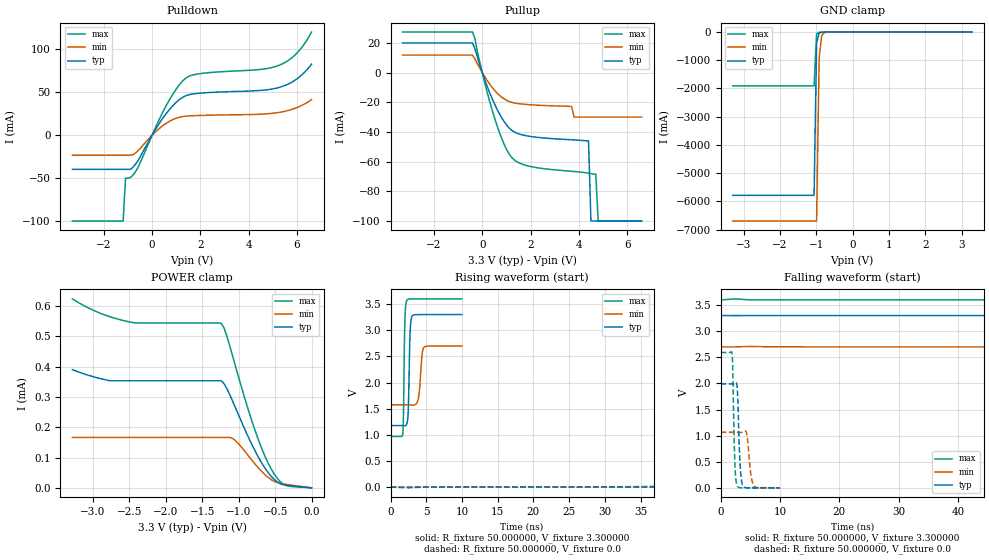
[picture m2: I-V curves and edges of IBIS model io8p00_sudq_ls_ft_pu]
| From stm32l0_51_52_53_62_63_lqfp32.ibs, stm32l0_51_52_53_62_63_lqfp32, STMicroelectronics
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|   Model io8p00_sudq_ls_ft_pu
[Model]  io8p00_sudq_ls_ft_pu
Model_type I/O
Polarity   Non-Inverting
Enable   Active-Low
Vinl =   0.990000V
Vinh =   2.310000V
Vmeas =  1.650000V
Cref =   50.000000pF
Rref =   100.000000M
Vref =   0.0V
C_comp   2.343000pF   2.309800pF   2.393900pF
[Temperature Range]   25.000000   0.125000k   -40.000000
[Pullup Reference]   3.300000V   2.700000V   3.600000V
[Pulldown Reference]   0.0V   0.0V   0.0V
[POWER Clamp Reference]   3.300000V   2.700000V   3.600000V
[GND Clamp Reference]   0.0V   0.0V   0.0V
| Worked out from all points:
|   slope of the pulldown table from 0 to 0.495 V, typ, clamps not added: 22.6 ohm
|   slope of the pullup table from 0 to 0.495 V, typ, clamps not added: 23.9 ohm
|   GND clamp passes 1 mA (typ) near -0.64 V on its own axis
|   rising waveform, R_fixture 50.000000, V_fixture 3.300000: 20-80 % time 207ps typ, 361ps min, 164ps max; typ from 1.18 V to 3.3 V
|   rising waveform, R_fixture 50.000000, V_fixture 0.0: 20-80 % time 205ns typ, 428ns min, 99.8ns max; typ from 0.001 V to 1.99 V
|   falling waveform, R_fixture 50.000000, V_fixture 3.300000: 20-80 % time 193ns typ, 383ns min, 106ns max; typ from 3.3 V to 1.18 V
|   falling waveform, R_fixture 50.000000, V_fixture 0.0: 20-80 % time 384ps typ, 554ps min, 307ps max; typ from 1.99 V to 0.001 V
[Pulldown]
|Voltage   I(typ)   I(min)   I(max)
-3.3V     -39.8mA    -23.38mA   -100mA
-1.2V     -39.8mA    -23.38mA   -100mA
-1.1V     -39.8mA    -23.38mA   -50.11mA
-900mV    -39.8mA    -23.38mA   -49.43mA
-700mV    -34.25mA   -21mA      -43.13mA
600mV     25.84mA    14.18mA    35.34mA
1V        38.32mA    19.82mA    53.81mA
1.4V      46.09mA    22.19mA    66.63mA
2V        49.05mA    23.02mA    71.83mA
5.2V      55.23mA    26.32mA    80.92mA
6V        65.77mA    32.26mA    95.84mA
6.6V      82.81mA    41.44mA    120.2mA
[Pullup]
|Voltage   I(typ)   I(min)   I(max)
-3.3V     19.9mA     11.73mA    27.27mA
-400mV    19.9mA     11.73mA    27.27mA
500mV     -20.88mA   -11.78mA   -30.07mA
1.2V      -38.62mA   -19.99mA   -56.79mA
1.9V      -42.8mA    -21.61mA   -62.92mA
3.7V      -45.29mA   -22.8mA    -66.51mA
3.8V      -45.39mA   -30mA      -66.64mA
4.4V      -46.01mA   -30mA      -67.77mA
4.5V      -100mA     -30mA      -68.06mA
4.7V      -100mA     -30mA      -68.4mA
4.8V      -100mA     -30mA      -100mA
6.6V      -100mA     -30mA      -100mA
[GND_clamp]
|Voltage   I(typ)   I(min)   I(max)
-3.3V     -5.787A    -6.696A    -1.906A
-1.06V    -5.787A    -6.696A    -1.906A
-990mV    -393.4mA   -6.696A    -70.75mA
-920mV    -33.02mA   -919.4mA   -10.9mA
-850mV    -6.829mA   -131.3mA   -6.521mA
-780mV    -3.478mA   -21.06mA   -4.208mA
3.28V     0A         0A         0A
[POWER_clamp]
|Voltage   I(typ)   I(min)   I(max)
-3.28V    390.5uA    166.4uA    624.1uA
-2.76V    353.6uA    166.4uA    564.6uA
-2.44V    353.6uA    166.4uA    545.3uA
-1.24V    353.6uA    166.4uA    543.5uA
-1.2V     344.2uA    166.4uA    528.2uA
-1.16V    327.1uA    166.4uA    499.5uA
-1.04V    262.6uA    155.2uA    398.8uA
-760mV    115.1uA    74.4uA     179.3uA
-560mV    39.86uA    27.94uA    65.07uA
-440mV    15uA       15.53uA    23.15uA
-360mV    8.745uA    12.05uA    9.089uA
0V        0A         0A         0A
[Ramp]
| variable   typ   min   max
dV/dt_r  1.19492/0.20471u   0.61229/0.42891u   1.55547/99.69141n
dV/dt_f  1.27200/0.19325u   0.63468/0.38283u   1.57747/0.10603u
R_load = 50.000000
[Rising Waveform]
R_fixture= 50.000000
V_fixture= 3.300000
V_fixture_min= 2.700000
V_fixture_max= 3.600000
|time   V(typ)   V(min)   V(max)
0s        1.178V     1.575V     970.9mV
1.702ns   1.178V     1.575V     1.018V
2.002ns   1.174V     1.575V     3.173V
2.282ns   1.215V     1.575V     3.571V
2.482ns   1.501V     1.575V     3.593V
2.743ns   2.98V      1.574V     3.598V
3.023ns   3.271V     1.57V      3.599V
3.904ns   3.299V     1.704V     3.599V
4.665ns   3.3V       2.672V     3.6V
9.97ns    3.3V       2.7V       3.6V
[Rising Waveform]
R_fixture= 50.000000
V_fixture= 0.0
V_fixture_min= 0.0
V_fixture_max= 0.0
|time   V(typ)   V(min)   V(max)
0s        1.061mV    1.816mV    656.8uV
50.05ns   4.552mV    4.549mV    91.28mV
100.1ns   80.19mV    4.692mV    919.5mV
165.2ns   461.5mV    7.663mV    1.935V
205.2ns   750.2mV    22.6mV     2.293V
255.3ns   1.09V      59.64mV    2.486V
385.4ns   1.671V     240.3mV    2.58V
505.5ns   1.883V     450.5mV    2.592V
823.3ns   1.986V     877.2mV    2.593V
1.246us   1.993V     1.064V     2.593V
[Falling Waveform]
R_fixture= 50.000000
V_fixture= 3.300000
V_fixture_min= 2.700000
V_fixture_max= 3.600000
|time   V(typ)   V(min)   V(max)
0s        3.3V       2.7V       3.6V
85.09ns   3.3V       2.7V       3.477V
145.1ns   3.215V     2.7V       2.595V
210.2ns   2.869V     2.697V     1.634V
247.7ns   2.614V     2.687V     1.255V
282.8ns   2.365V     2.669V     1.096V
392.9ns   1.648V     2.554V     1V
488ns     1.351V     2.4V       982.1mV
808.3ns   1.2V       1.82V      971.6mV
1.246us   1.178V     1.575V     970.9mV
[Falling Waveform]
R_fixture= 50.000000
V_fixture= 0.0
V_fixture_min= 0.0
V_fixture_max= 0.0
|time   V(typ)   V(min)   V(max)
0s        1.993V     1.064V     2.593V
1.922ns   1.993V     1.064V     2.565V
2.022ns   1.992V     1.064V     2.313V
2.382ns   1.997V     1.064V     499.2mV
2.783ns   1.917V     1.064V     41.24mV
3.243ns   509.5mV    1.064V     2.891mV
3.664ns   60.15mV    1.066V     891.9uV
4.404ns   2.172mV    1.027V     746.8uV
5.546ns   1.117mV    47.38mV    695.1uV
9.97ns    1.061mV    1.816mV    656.8uV
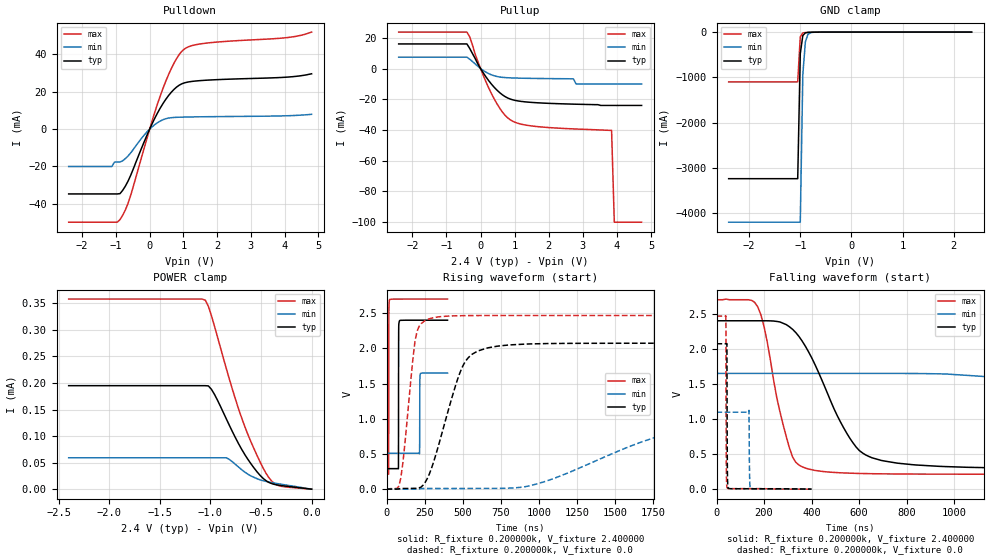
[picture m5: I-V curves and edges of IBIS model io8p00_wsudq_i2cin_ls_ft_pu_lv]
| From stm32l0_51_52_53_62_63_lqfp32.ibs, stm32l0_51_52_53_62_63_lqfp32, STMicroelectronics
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|   Model io8p00_wsudq_i2cin_ls_ft_pu_lv
[Model]  io8p00_wsudq_i2cin_ls_ft_pu_lv
Model_type I/O
Polarity   Non-Inverting
Enable   Active-Low
Vinl =   0.720000V
Vinh =   1.680000V
Vmeas =  1.200000V
Cref =   50.000000pF
Rref =   100.000000M
Vref =   0.0V
C_comp   2.943600pF   2.919700pF   2.965100pF
[Temperature Range]   25.000000   0.105000k   -40.000000
[Pullup Reference]   2.400000V   1.650000V   2.700000V
[Pulldown Reference]   0.0V   0.0V   0.0V
[POWER Clamp Reference]   2.400000V   1.650000V   2.700000V
[GND Clamp Reference]   0.0V   0.0V   0.0V
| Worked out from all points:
|   slope of the pulldown table from 0 to 0.36 V, typ, clamps not added: 28.5 ohm
|   slope of the pullup table from 0 to 0.36 V, typ, clamps not added: 32.2 ohm
|   GND clamp passes 1 mA (typ) near -0.65 V on its own axis
|   rising waveform, R_fixture 0.200000k, V_fixture 2.400000: 20-80 % time 676ps typ, 843ps min, 761ps max; typ from 0.292 V to 2.4 V
|   rising waveform, R_fixture 0.200000k, V_fixture 0.0: 20-80 % time 170ns typ, 820ns min, 66.7ns max; typ from 0.001 V to 2.07 V
|   falling waveform, R_fixture 0.200000k, V_fixture 2.400000: 20-80 % time 180ns typ, 729ns min, 89.6ns max; typ from 2.4 V to 0.292 V
|   falling waveform, R_fixture 0.200000k, V_fixture 0.0: 20-80 % time 1.27ns typ, 1.78ns min, 1.06ns max; typ from 2.07 V to 0.001 V
[Pulldown]
|Voltage   I(typ)   I(min)   I(max)
-2.4V     -34.7mA    -20mA      -49.82mA
-1.12V    -34.7mA    -20mA      -49.82mA
-1.04V    -34.7mA    -17.61mA   -49.82mA
-880mV    -34.55mA   -17.61mA   -48.46mA
-560mV    -24.65mA   -12.68mA   -35.33mA
0V        0A         0A         0A
400mV     13.84mA    5.066mA    22.03mA
720mV     21.25mA    6.254mA    35.26mA
1.04V     24.83mA    6.464mA    43.02mA
1.6V      26.11mA    6.627mA    45.88mA
4V        27.76mA    7.125mA    48.87mA
4.8V      29.63mA    7.94mA     51.96mA
[Pullup]
|Voltage   I(typ)   I(min)   I(max)
-2.4V     16.03mA    7.415mA    23.74mA
-400mV    16.03mA    7.415mA    23.74mA
80mV      -2.838mA   -1.261mA   -4.478mA
320mV     -10.16mA   -4.078mA   -16.34mA
640mV     -17.08mA   -5.718mA   -28.28mA
960mV     -20.45mA   -6.128mA   -34.49mA
1.76V     -22.39mA   -6.47mA    -37.97mA
2.72V     -23.16mA   -6.7mA     -39.27mA
2.8V      -23.2mA    -10mA      -39.35mA
3.84V     -24mA      -10mA      -40.2mA
3.92V     -24mA      -10mA      -100mA
4.72V     -24mA      -10mA      -100mA
[GND_clamp]
|Voltage   I(typ)   I(min)   I(max)
-2.4V     -3.237A    -4.198A    -1.1A
-1.05V    -3.237A    -4.198A    -1.1A
-1V       -475.8mA   -4.198A    -104.2mA
-950mV    -76.24mA   -935.4mA   -18.39mA
-900mV    -16.61mA   -212.9mA   -9.105mA
-850mV    -6.547mA   -50.94mA   -6.589mA
-800mV    -3.998mA   -13.81mA   -4.86mA
-650mV    -1.043mA   -1.182mA   -1.146mA
2.35V     0A         0A         0A
[POWER_clamp]
|Voltage   I(typ)   I(min)   I(max)
-2.4V     195uA      59.14uA    358.2uA
-1.05V    195uA      59.14uA    356uA
-1.02V    194.5uA    59.14uA    344.5uA
-960mV    178.7uA    59.14uA    307.4uA
-840mV    131.4uA    59.14uA    225.5uA
-690mV    74.82uA    36.58uA    133.7uA
-600mV    48.08uA    24.92uA    89.53uA
-510mV    26.23uA    17.69uA    51.64uA
-450mV    15.91uA    14.53uA    29.77uA
-390mV    10.19uA    12.23uA    14.39uA
-330mV    7.608uA    10.24uA    6.963uA
0V        0A         0A         0A
[Ramp]
| variable   typ   min   max
dV/dt_r  0.65095/0.30115u   0.19035/0.81858u   1.03799/0.14356u
dV/dt_f  0.75618/0.32152u   0.19644/0.84673u   1.13779/0.15984u
R_load = 50.000000
[Rising Waveform]
R_fixture= 0.200000k
V_fixture= 2.400000
V_fixture_min= 1.650000
V_fixture_max= 2.700000
|time   V(typ)   V(min)   V(max)
0s        292mV      510.8mV    213.5mV
14.01ns   292mV      510.8mV    220.4mV
15.22ns   292mV      510.8mV    2.419V
19.22ns   292mV      510.8mV    2.687V
77.68ns   290.2mV    510.8mV    2.7V
79.68ns   2.256V     510.8mV    2.7V
84.08ns   2.386V     510.8mV    2.7V
216.2ns   2.4V       506mV      2.7V
221.8ns   2.4V       1.638V     2.7V
400ns     2.4V       1.65V      2.7V
[Rising Waveform]
R_fixture= 0.200000k
V_fixture= 0.0
V_fixture_min= 0.0
V_fixture_max= 0.0
|time   V(typ)   V(min)   V(max)
0s        1.171mV    2.207mV    629.1uV
93.43ns   10.52mV    2.207mV    156.3mV
200.2ns   13.28mV    2.207mV    2.243V
266.9ns   150.1mV    9.996mV    2.408V
347ns     668.1mV    9.997mV    2.449V
533.9ns   1.862V     10.12mV    2.465V
920.9ns   2.062V     40.68mV    2.467V
1.949us   2.073V     854.1mV    2.467V
2.696us   2.073V     1.055V     2.467V
13.33us   2.073V     1.097V     2.467V
[Falling Waveform]
R_fixture= 0.200000k
V_fixture= 2.400000
V_fixture_min= 1.650000
V_fixture_max= 2.700000
|time   V(typ)   V(min)   V(max)
0s        2.4V       1.65V      2.7V
173.5ns   2.4V       1.65V      2.598V
320.3ns   2.277V     1.65V      457.3mV
520.5ns   964.7mV    1.65V      234mV
627.3ns   488.6mV    1.65V      222.7mV
827.5ns   348.5mV    1.649V     215.8mV
1.335us   298.6mV    1.507V     213.6mV
2.202us   292.3mV    723.9mV    213.5mV
2.829us   292mV      567.8mV    213.5mV
13.33us   292mV      510.8mV    213.5mV
[Falling Waveform]
R_fixture= 0.200000k
V_fixture= 0.0
V_fixture_min= 0.0
V_fixture_max= 0.0
|time   V(typ)   V(min)   V(max)
0s        2.073V     1.097V     2.467V
39.24ns   2.073V     1.097V     2.471V
41.24ns   2.073V     1.097V     298.9mV
43.64ns   2.071V     1.097V     33.15mV
44.84ns   728.6mV    1.097V     20.42mV
48.85ns   20.84mV    1.097V     10.89mV
136.5ns   6.533mV    1.123V     8.385mV
139.3ns   6.534mV    162mV      8.381mV
143.3ns   6.534mV    9.087mV    8.377mV
400ns     1.171mV    2.207mV    629.1uV
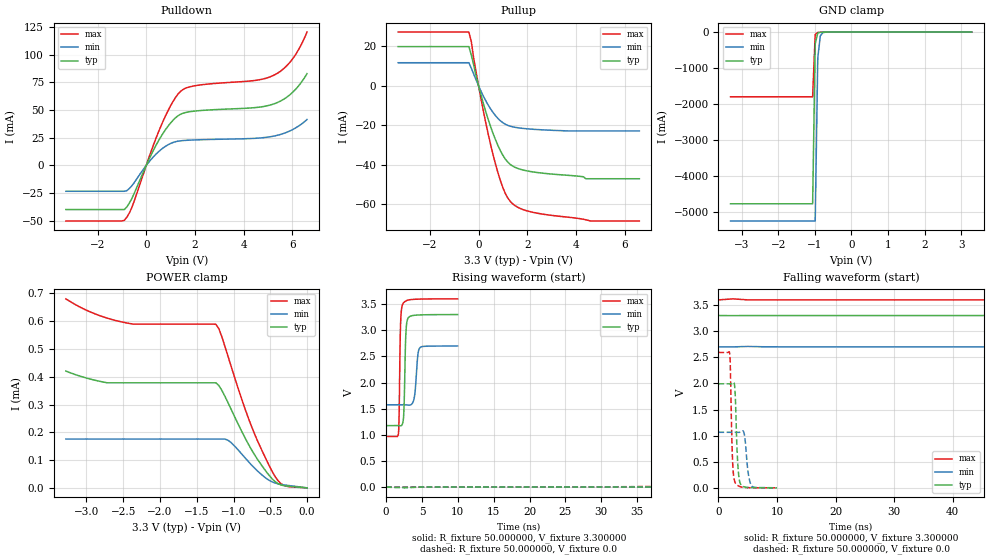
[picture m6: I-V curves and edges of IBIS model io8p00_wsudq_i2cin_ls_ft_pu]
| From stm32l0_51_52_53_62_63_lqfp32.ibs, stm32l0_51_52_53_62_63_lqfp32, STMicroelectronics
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|   Model io8p00_wsudq_i2cin_ls_ft_pu
[Model]  io8p00_wsudq_i2cin_ls_ft_pu
Model_type I/O
Polarity   Non-Inverting
Enable   Active-Low
Vinl =   0.990000V
Vinh =   2.310000V
Vmeas =  1.650000V
Cref =   50.000000pF
Rref =   100.000000M
Vref =   0.0V
C_comp   3.020400pF   2.988200pF   3.054500pF
[Temperature Range]   25.000000   0.125000k   -40.000000
[Pullup Reference]   3.300000V   2.700000V   3.600000V
[Pulldown Reference]   0.0V   0.0V   0.0V
[POWER Clamp Reference]   3.300000V   2.700000V   3.600000V
[GND Clamp Reference]   0.0V   0.0V   0.0V
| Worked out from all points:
|   slope of the pulldown table from 0 to 0.495 V, typ, clamps not added: 22.6 ohm
|   slope of the pullup table from 0 to 0.495 V, typ, clamps not added: 23.9 ohm
|   GND clamp passes 1 mA (typ) near -0.64 V on its own axis
|   rising waveform, R_fixture 50.000000, V_fixture 3.300000: 20-80 % time 222ps typ, 369ps min, 182ps max; typ from 1.18 V to 3.3 V
|   rising waveform, R_fixture 50.000000, V_fixture 0.0: 20-80 % time 204ns typ, 424ns min, 99.2ns max; typ from 0.001 V to 1.99 V
|   falling waveform, R_fixture 50.000000, V_fixture 3.300000: 20-80 % time 192ns typ, 379ns min, 105ns max; typ from 3.3 V to 1.18 V
|   falling waveform, R_fixture 50.000000, V_fixture 0.0: 20-80 % time 410ps typ, 575ps min, 333ps max; typ from 1.99 V to 0.001 V
[Pulldown]
|Voltage   I(typ)   I(min)   I(max)
-3.3V     -39.83mA   -23.36mA   -50.2mA
-900mV    -39.83mA   -23.36mA   -49.52mA
-600mV    -30.28mA   -18.59mA   -38.45mA
100mV     4.867mA    2.821mA    6.48mA
600mV     25.85mA    14.17mA    35.39mA
1V        38.33mA    19.81mA    53.88mA
1.4V      46.1mA     22.18mA    66.72mA
2V        49.07mA    23.02mA    71.93mA
4.4V      52.05mA    24.38mA    76.53mA
5.2V      55.25mA    26.3mA     81.02mA
6V        65.78mA    32.24mA    95.96mA
6.6V      82.83mA    41.41mA    120.4mA
[Pullup]
|Voltage   I(typ)   I(min)   I(max)
-3.3V     19.9mA     11.73mA    27.27mA
-400mV    19.9mA     11.73mA    27.27mA
-300mV    15.74mA    8.978mA    22.52mA
-200mV    10.44mA    5.968mA    13.84mA
200mV     -9.115mA   -5.294mA   -12.98mA
600mV     -24.29mA   -13.56mA   -35.12mA
1V        -35.2mA    -18.69mA   -51.63mA
1.2V      -38.62mA   -19.99mA   -56.79mA
1.4V      -40.6mA    -20.72mA   -59.71mA
2.2V      -43.48mA   -21.92mA   -63.91mA
4.6V      -47mA      -22.8mA    -68.4mA
6.6V      -47mA      -22.8mA    -68.4mA
[GND_clamp]
|Voltage   I(typ)   I(min)   I(max)
-3.3V     -4.766A    -5.244A    -1.797A
-1.06V    -4.766A    -5.244A    -1.797A
-990mV    -326.6mA   -5.244A    -67.9mA
-920mV    -28.92mA   -722.1mA   -10.96mA
-850mV    -6.612mA   -104.2mA   -6.532mA
-780mV    -3.464mA   -17.27mA   -4.209mA
-500mV    -57.88uA   -167.8uA   -34.02uA
3.28V     0A         0A         0A
[POWER_clamp]
|Voltage   I(typ)   I(min)   I(max)
-3.28V    420.5uA    175.8uA    680.6uA
-2.72V    378.4uA    175.8uA    611.4uA
-2.4V     378.3uA    175.8uA    591.2uA
-1.24V    378.3uA    175.8uA    588.9uA
-1.2V     368.9uA    175.8uA    573.6uA
-1.08V    309.6uA    172.2uA    478.3uA
-920mV    220.5uA    131.5uA    344.5uA
-760mV    139.7uA    83.77uA    224.7uA
-480mV    33.95uA    22.2uA     61.82uA
-400mV    15.86uA    14.74uA    27.74uA
-320mV    8.147uA    10.83uA    9.34uA
0V        0A         0A         0A
[Ramp]
| variable   typ   min   max
dV/dt_r  1.19492/0.20379u   0.61289/0.42639u   1.55547/99.12215n
dV/dt_f  1.27224/0.19143u   0.63576/0.37936u   1.57815/0.10502u
R_load = 50.000000
[Rising Waveform]
R_fixture= 50.000000
V_fixture= 3.300000
V_fixture_min= 2.700000
V_fixture_max= 3.600000
|time   V(typ)   V(min)   V(max)
0s        1.178V     1.575V     969.7mV
1.702ns   1.177V     1.575V     1.016V
2.022ns   1.174V     1.575V     3.157V
2.342ns   1.245V     1.575V     3.508V
2.503ns   1.572V     1.575V     3.536V
2.743ns   2.916V     1.574V     3.559V
3.023ns   3.223V     1.571V     3.575V
3.884ns   3.285V     1.688V     3.591V
4.745ns   3.293V     2.671V     3.596V
9.97ns    3.3V       2.7V       3.6V
[Rising Waveform]
R_fixture= 50.000000
V_fixture= 0.0
V_fixture_min= 0.0
V_fixture_max= 0.0
|time   V(typ)   V(min)   V(max)
0s        1.061mV    1.817mV    656.1uV
50.05ns   4.462mV    4.547mV    93.9mV
100.1ns   82.2mV     4.583mV    928.5mV
162.7ns   449.3mV    8.852mV    1.915V
202.7ns   739mV      24.93mV    2.283V
250.2ns   1.067V     55.94mV    2.478V
370.4ns   1.632V     218.1mV    2.577V
500.5ns   1.881V     445.4mV    2.591V
873.4ns   1.989V     919.2mV    2.593V
1.246us   1.993V     1.064V     2.593V
[Falling Waveform]
R_fixture= 50.000000
V_fixture= 3.300000
V_fixture_min= 2.700000
V_fixture_max= 3.600000
|time   V(typ)   V(min)   V(max)
0s        3.3V       2.7V       3.6V
82.58ns   3.3V       2.7V       3.49V
150.2ns   3.19V      2.7V       2.488V
212.7ns   2.838V     2.697V     1.578V
247.7ns   2.597V     2.687V     1.237V
285.3ns   2.327V     2.665V     1.083V
410.4ns   1.545V     2.523V     993.3mV
518ns     1.312V     2.335V     977.9mV
825.8ns   1.196V     1.792V     970.3mV
1.246us   1.178V     1.575V     969.7mV
[Falling Waveform]
R_fixture= 50.000000
V_fixture= 0.0
V_fixture_min= 0.0
V_fixture_max= 0.0
|time   V(typ)   V(min)   V(max)
0s        1.993V     1.064V     2.593V
1.922ns   1.993V     1.064V     2.566V
2.402ns   1.998V     1.064V     529mV
2.843ns   1.817V     1.064V     101.2mV
3.263ns   520.4mV    1.064V     47.12mV
3.724ns   85mV       1.067V     22.21mV
4.404ns   19mV       1.031V     7.616mV
5.045ns   7.992mV    313.8mV    4.607mV
5.666ns   4.495mV    37.82mV    3.295mV
9.97ns    1.061mV    1.817mV    656.1uV
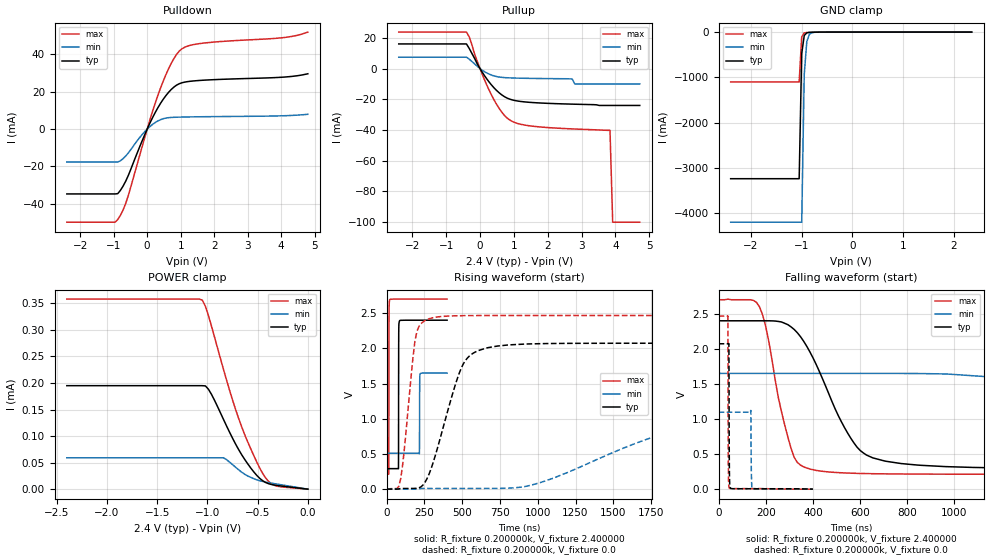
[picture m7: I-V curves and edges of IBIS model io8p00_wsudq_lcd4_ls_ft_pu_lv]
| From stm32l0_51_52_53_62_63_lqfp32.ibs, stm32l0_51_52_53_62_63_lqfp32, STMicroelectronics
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|   Model io8p00_wsudq_lcd4_ls_ft_pu_lv
[Model]  io8p00_wsudq_lcd4_ls_ft_pu_lv
Model_type I/O
Polarity   Non-Inverting
Enable   Active-Low
Vinl =   0.720000V
Vinh =   1.680000V
Vmeas =  1.200000V
Cref =   50.000000pF
Rref =   100.000000M
Vref =   0.0V
C_comp   3.178800pF   3.170000pF   3.206700pF
[Temperature Range]   25.000000   0.105000k   -40.000000
[Pullup Reference]   2.400000V   1.650000V   2.700000V
[Pulldown Reference]   0.0V   0.0V   0.0V
[POWER Clamp Reference]   2.400000V   1.650000V   2.700000V
[GND Clamp Reference]   0.0V   0.0V   0.0V
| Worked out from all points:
|   slope of the pulldown table from 0 to 0.36 V, typ, clamps not added: 28.5 ohm
|   slope of the pullup table from 0 to 0.36 V, typ, clamps not added: 32.2 ohm
|   GND clamp passes 1 mA (typ) near -0.64 V on its own axis
|   rising waveform, R_fixture 0.200000k, V_fixture 2.400000: 20-80 % time 729ps typ, 875ps min, 832ps max; typ from 0.292 V to 2.4 V
|   rising waveform, R_fixture 0.200000k, V_fixture 0.0: 20-80 % time 169ns typ, 818ns min, 66.7ns max; typ from 0.001 V to 2.07 V
|   falling waveform, R_fixture 0.200000k, V_fixture 2.400000: 20-80 % time 180ns typ, 728ns min, 89.5ns max; typ from 2.4 V to 0.292 V
|   falling waveform, R_fixture 0.200000k, V_fixture 0.0: 20-80 % time 1.32ns typ, 1.82ns min, 1.12ns max; typ from 2.07 V to 0.001 V
[Pulldown]
|Voltage   I(typ)   I(min)   I(max)
-2.4V     -34.7mA    -17.6mA    -49.82mA
-960mV    -34.7mA    -17.6mA    -49.82mA
-880mV    -34.55mA   -17.6mA    -48.46mA
-720mV    -30.52mA   -15.8mA    -43.27mA
-560mV    -24.65mA   -12.68mA   -35.33mA
0V        0A         0A         0A
400mV     13.84mA    5.066mA    22.03mA
720mV     21.25mA    6.254mA    35.26mA
1.04V     24.83mA    6.464mA    43.02mA
1.6V      26.11mA    6.627mA    45.88mA
4V        27.76mA    7.125mA    48.87mA
4.8V      29.63mA    7.94mA     51.96mA
[Pullup]
|Voltage   I(typ)   I(min)   I(max)
-2.4V     16.03mA    7.415mA    23.74mA
-400mV    16.03mA    7.415mA    23.74mA
80mV      -2.838mA   -1.261mA   -4.478mA
320mV     -10.16mA   -4.078mA   -16.34mA
640mV     -17.08mA   -5.718mA   -28.28mA
960mV     -20.45mA   -6.128mA   -34.49mA
1.76V     -22.39mA   -6.47mA    -37.97mA
2.72V     -23.16mA   -6.7mA     -39.27mA
2.8V      -23.2mA    -10mA      -39.35mA
3.84V     -24mA      -10mA      -40.2mA
3.92V     -24mA      -10mA      -100mA
4.72V     -24mA      -10mA      -100mA
[GND_clamp]
|Voltage   I(typ)   I(min)   I(max)
-2.4V     -3.238A    -4.199A    -1.101A
-1.05V    -3.238A    -4.199A    -1.101A
-1V       -476.5mA   -4.199A    -104.7mA
-950mV    -76.68mA   -936.1mA   -18.74mA
-900mV    -16.85mA   -213.2mA   -9.358mA
-850mV    -6.706mA   -51.12mA   -6.778mA
-800mV    -4.108mA   -13.92mA   -4.995mA
-650mV    -1.07mA    -1.211mA   -1.175mA
2.35V     0A         0A         0A
[POWER_clamp]
|Voltage   I(typ)   I(min)   I(max)
-2.4V     195uA      59.14uA    358.2uA
-1.05V    195uA      59.14uA    356uA
-1.02V    194.5uA    59.14uA    344.5uA
-960mV    178.7uA    59.14uA    307.4uA
-840mV    131.4uA    59.14uA    225.5uA
-690mV    74.82uA    36.58uA    133.7uA
-600mV    48.08uA    24.92uA    89.53uA
-510mV    26.23uA    17.69uA    51.64uA
-450mV    15.91uA    14.53uA    29.77uA
-390mV    10.19uA    12.23uA    14.39uA
-330mV    7.608uA    10.25uA    6.963uA
0V        0A         0A         0A
[Ramp]
| variable   typ   min   max
dV/dt_r  0.65095/0.30074u   0.19035/0.81549u   1.03799/0.14368u
dV/dt_f  0.75618/0.32116u   0.19644/0.84580u   1.13779/0.15969u
R_load = 50.000000
[Rising Waveform]
R_fixture= 0.200000k
V_fixture= 2.400000
V_fixture_min= 1.650000
V_fixture_max= 2.700000
|time   V(typ)   V(min)   V(max)
0s        292mV      510.8mV    213.5mV
14.01ns   292mV      510.8mV    220.5mV
15.22ns   292mV      510.8mV    2.344V
19.62ns   292mV      510.8mV    2.688V
77.68ns   290.2mV    510.8mV    2.7V
79.68ns   2.212V     510.8mV    2.7V
84.08ns   2.385V     510.8mV    2.7V
216.2ns   2.4V       506mV      2.7V
222.2ns   2.4V       1.639V     2.7V
400ns     2.4V       1.65V      2.7V
[Rising Waveform]
R_fixture= 0.200000k
V_fixture= 0.0
V_fixture_min= 0.0
V_fixture_max= 0.0
|time   V(typ)   V(min)   V(max)
0s        1.171mV    2.207mV    629.1uV
93.43ns   10.52mV    2.207mV    155.8mV
200.2ns   12.07mV    2.207mV    2.242V
280.3ns   213.3mV    9.996mV    2.42V
360.4ns   771.6mV    9.997mV    2.451V
533.9ns   1.862V     10.05mV    2.465V
920.9ns   2.061V     40.57mV    2.467V
1.869us   2.073V     808.5mV    2.467V
2.736us   2.073V     1.059V     2.467V
13.33us   2.073V     1.097V     2.467V
[Falling Waveform]
R_fixture= 0.200000k
V_fixture= 2.400000
V_fixture_min= 1.650000
V_fixture_max= 2.700000
|time   V(typ)   V(min)   V(max)
0s        2.4V       1.65V      2.7V
173.5ns   2.4V       1.65V      2.598V
320.3ns   2.277V     1.65V      455.4mV
520.5ns   962mV      1.65V      234mV
627.3ns   486.4mV    1.65V      222.7mV
840.8ns   344.9mV    1.648V     215.6mV
1.335us   298.7mV    1.507V     213.6mV
2.189us   292.2mV    730.1mV    213.5mV
2.95us    292mV      556.4mV    213.5mV
13.33us   292mV      510.8mV    213.5mV
[Falling Waveform]
R_fixture= 0.200000k
V_fixture= 0.0
V_fixture_min= 0.0
V_fixture_max= 0.0
|time   V(typ)   V(min)   V(max)
0s        2.073V     1.097V     2.467V
39.24ns   2.073V     1.097V     2.471V
41.24ns   2.073V     1.097V     324.8mV
43.64ns   2.071V     1.097V     35.85mV
44.84ns   759.3mV    1.097V     21.21mV
49.25ns   18.53mV    1.097V     10.6mV
136.5ns   6.56mV     1.122V     8.406mV
139.3ns   6.56mV     169.2mV    8.406mV
143.3ns   6.56mV     9.483mV    8.407mV
400ns     1.171mV    2.207mV    629.1uV
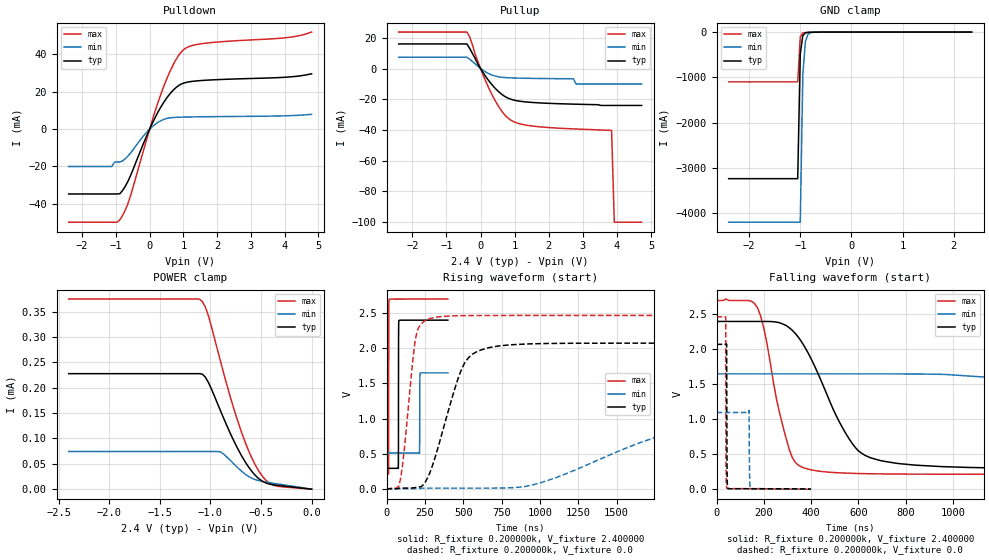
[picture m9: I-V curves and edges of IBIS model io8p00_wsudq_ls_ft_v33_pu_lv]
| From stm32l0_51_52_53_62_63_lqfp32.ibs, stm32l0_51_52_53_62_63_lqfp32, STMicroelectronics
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|   Model io8p00_wsudq_ls_ft_v33_pu_lv
[Model]  io8p00_wsudq_ls_ft_v33_pu_lv
Model_type I/O
Polarity   Non-Inverting
Enable   Active-Low
Vinl =   0.720000V
Vinh =   1.680000V
Vmeas =  1.200000V
Cref =   50.000000pF
Rref =   100.000000M
Vref =   0.0V
C_comp   2.582000pF   2.574200pF   2.601000pF
[Temperature Range]   25.000000   0.105000k   -40.000000
[Pullup Reference]   2.400000V   1.650000V   2.700000V
[Pulldown Reference]   0.0V   0.0V   0.0V
[POWER Clamp Reference]   2.400000V   1.650000V   2.700000V
[GND Clamp Reference]   0.0V   0.0V   0.0V
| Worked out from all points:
|   slope of the pulldown table from 0 to 0.36 V, typ, clamps not added: 28.5 ohm
|   slope of the pullup table from 0 to 0.36 V, typ, clamps not added: 32.2 ohm
|   GND clamp passes 1 mA (typ) near -0.65 V on its own axis
|   rising waveform, R_fixture 0.200000k, V_fixture 2.400000: 20-80 % time 670ps typ, 828ps min, 645ps max; typ from 0.292 V to 2.4 V
|   rising waveform, R_fixture 0.200000k, V_fixture 0.0: 20-80 % time 169ns typ, 821ns min, 66.7ns max; typ from 0.001 V to 2.07 V
|   falling waveform, R_fixture 0.200000k, V_fixture 2.400000: 20-80 % time 180ns typ, 728ns min, 89.6ns max; typ from 2.4 V to 0.292 V
|   falling waveform, R_fixture 0.200000k, V_fixture 0.0: 20-80 % time 1.24ns typ, 1.74ns min, 1.02ns max; typ from 2.07 V to 0.001 V
[Pulldown]
|Voltage   I(typ)   I(min)   I(max)
-2.4V     -34.71mA   -20mA      -49.82mA
-1.12V    -34.71mA   -20mA      -49.82mA
-1.04V    -34.71mA   -17.61mA   -49.82mA
-880mV    -34.55mA   -17.61mA   -48.46mA
-560mV    -24.65mA   -12.68mA   -35.33mA
0V        0A         0A         0A
400mV     13.84mA    5.066mA    22.03mA
720mV     21.25mA    6.254mA    35.26mA
1.04V     24.83mA    6.464mA    43.02mA
1.6V      26.11mA    6.627mA    45.88mA
4V        27.76mA    7.125mA    48.88mA
4.8V      29.64mA    7.94mA     51.96mA
[Pullup]
|Voltage   I(typ)   I(min)   I(max)
-2.4V     16.03mA    7.415mA    23.74mA
-400mV    16.03mA    7.415mA    23.74mA
80mV      -2.838mA   -1.261mA   -4.478mA
320mV     -10.16mA   -4.078mA   -16.34mA
640mV     -17.08mA   -5.718mA   -28.28mA
960mV     -20.45mA   -6.128mA   -34.49mA
1.76V     -22.39mA   -6.47mA    -37.97mA
2.72V     -23.16mA   -6.63mA    -39.27mA
2.8V      -23.2mA    -10mA      -39.35mA
3.84V     -24mA      -10mA      -40.2mA
3.92V     -24mA      -10mA      -100mA
4.72V     -24mA      -10mA      -100mA
[GND_clamp]
|Voltage   I(typ)   I(min)   I(max)
-2.4V     -3.237A    -4.198A    -1.1A
-1.05V    -3.237A    -4.198A    -1.1A
-1V       -475.9mA   -4.198A    -104.3mA
-950mV    -76.36mA   -935.5mA   -18.56mA
-900mV    -16.77mA   -213mA     -9.293mA
-850mV    -6.713mA   -51.08mA   -6.724mA
-800mV    -4.108mA   -13.94mA   -4.924mA
-650mV    -1.048mA   -1.2mA     -1.149mA
2.35V     0A         0A         0A
[POWER_clamp]
|Voltage   I(typ)   I(min)   I(max)
-2.4V     228uA      74.29uA    375.2uA
-1.11V    228uA      74.29uA    375.2uA
-1.08V    227.1uA    74.29uA    370.5uA
-1.02V    210.9uA    74.29uA    342.6uA
-900mV    154.7uA    73.58uA    252.2uA
-810mV    113.1uA    58.15uA    186.8uA
-720mV    76.17uA    40.44uA    128.5uA
-630mV    45.92uA    26.04uA    79.56uA
-540mV    23.97uA    17.88uA    41.93uA
-450mV    12.07uA    14.02uA    17.32uA
-390mV    9.04uA     12.05uA    8.867uA
0V        0A         0A         0A
[Ramp]
| variable   typ   min   max
dV/dt_r  0.65095/0.30173u   0.19035/0.81890u   1.03799/0.14353u
dV/dt_f  0.75618/0.32134u   0.19644/0.84588u   1.13779/0.15978u
R_load = 50.000000
[Rising Waveform]
R_fixture= 0.200000k
V_fixture= 2.400000
V_fixture_min= 1.650000
V_fixture_max= 2.700000
|time   V(typ)   V(min)   V(max)
0s        292mV      510.8mV    213.5mV
13.21ns   292mV      510.8mV    212.1mV
14.41ns   292mV      510.8mV    2.268V
16.82ns   292mV      510.8mV    2.693V
76.88ns   290.2mV    510.8mV    2.7V
78.48ns   2.101V     510.8mV    2.7V
80.88ns   2.393V     510.8mV    2.7V
215ns     2.4V       505.2mV    2.7V
219.4ns   2.4V       1.645V     2.7V
400ns     2.4V       1.65V      2.7V
[Rising Waveform]
R_fixture= 0.200000k
V_fixture= 0.0
V_fixture_min= 0.0
V_fixture_max= 0.0
|time   V(typ)   V(min)   V(max)
0s        1.171mV    2.207mV    629.1uV
93.43ns   10.52mV    2.207mV    163.1mV
200.2ns   22.06mV    2.207mV    2.247V
280.3ns   217.4mV    9.996mV    2.42V
373.7ns   882.5mV    9.996mV    2.454V
533.9ns   1.863V     10.17mV    2.465V
920.9ns   2.062V     40.96mV    2.467V
1.922us   2.073V     840.1mV    2.467V
2.736us   2.073V     1.059V     2.467V
13.33us   2.073V     1.097V     2.467V
[Falling Waveform]
R_fixture= 0.200000k
V_fixture= 2.400000
V_fixture_min= 1.650000
V_fixture_max= 2.700000
|time   V(typ)   V(min)   V(max)
0s        2.4V       1.65V      2.7V
160.2ns   2.4V       1.65V      2.66V
320.3ns   2.274V     1.65V      453.9mV
507.2ns   1.046V     1.65V      236.1mV
627.3ns   486.3mV    1.65V      222.5mV
840.8ns   344.3mV    1.648V     215.7mV
1.335us   298.6mV    1.508V     213.6mV
2.189us   292.2mV    731.1mV    213.5mV
2.963us   292mV      555.4mV    213.5mV
13.33us   292mV      510.8mV    213.5mV
[Falling Waveform]
R_fixture= 0.200000k
V_fixture= 0.0
V_fixture_min= 0.0
V_fixture_max= 0.0
|time   V(typ)   V(min)   V(max)
0s        2.073V     1.097V     2.467V
38.44ns   2.073V     1.097V     2.467V
40.44ns   2.073V     1.097V     282.5mV
42.84ns   2.062V     1.097V     24.37mV
43.64ns   1.029V     1.097V     15.76mV
45.25ns   126.5mV    1.097V     10.18mV
48.85ns   12.34mV    1.097V     8.436mV
137.3ns   6.61mV     1.128V     8.378mV
144.1ns   6.61mV     7.743mV    8.37mV
400ns     1.171mV    2.207mV    629.1uV
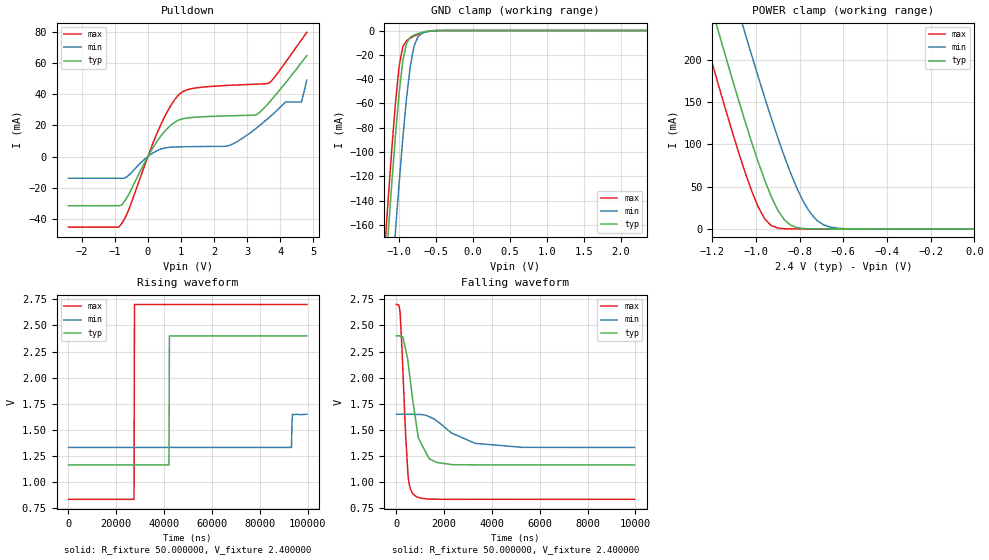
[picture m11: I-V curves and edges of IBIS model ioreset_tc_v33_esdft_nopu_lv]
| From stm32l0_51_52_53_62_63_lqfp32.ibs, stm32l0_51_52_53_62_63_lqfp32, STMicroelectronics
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|   Model ioreset_tc_v33_esdft_nopu_lv
[Model]  ioreset_tc_v33_esdft_nopu_lv
Model_type I/O_open_drain
Polarity   Inverting
Enable   Active-High
Vinl =   0.720000V
Vinh =   1.680000V
Vmeas =  1.200000V
Cref =   1.0000000000000001E-7F
Rref =   1.000000k
Vref =   2.400000V
C_comp   1.925200pF   1.905500pF   1.943400pF
[Temperature Range]   25.000000   0.125000k   -40.000000
[Pullup Reference]   2.400000V   1.650000V   2.700000V
[Pulldown Reference]   0.0V   0.0V   0.0V
[POWER Clamp Reference]   2.400000V   1.650000V   2.700000V
[GND Clamp Reference]   0.0V   0.0V   0.0V
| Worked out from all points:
|   slope of the pulldown table from 0 to 0.36 V, typ, clamps not added: 29.5 ohm
|   GND clamp passes 1 mA (typ) near -0.65 V on its own axis
|   POWER clamp passes 1 mA (typ) near -0.79 V on its own axis
|   rising waveform, R_fixture 50.000000, V_fixture 2.400000: 20-80 % time 120ns typ, 213ns min, 120ns max; typ from 1.17 V to 2.4 V
|   falling waveform, R_fixture 50.000000, V_fixture 2.400000: 20-80 % time 455ns typ, 1.36us min, 227ns max; typ from 2.4 V to 1.17 V
[Pulldown]
|Voltage   I(typ)   I(min)   I(max)
-2.4V     -31.61mA   -13.97mA   -45.4mA
-880mV    -31.61mA   -13.97mA   -45.4mA
-560mV    -23.65mA   -11.7mA    -33.24mA
0V        -8.188pA   -7.28pA    -13.59pA
400mV     13.38mA    4.819mA    20.92mA
960mV     23.69mA    6.215mA    40.22mA
2.4V      26.12mA    6.776mA    45.67mA
3.28V     26.92mA    18.27mA    46.49mA
3.68V     35.13mA    25.4mA     47.5mA
4.16V     47.39mA    35mA       60.62mA
4.64V     60.4mA     35mA       74.99mA
4.8V      64.8mA     49.1mA     79.8mA
[GND_clamp]
|Voltage   I(typ)   I(min)   I(max)
-2.4V     -1.363A    -1.438A    -1.343A
-1.2V     -211.8mA   -294.7mA   -184.3mA
-1.15V    -168.1mA   -250.5mA   -140.2mA
-1.05V    -86.49mA   -165.5mA   -59.93mA
-1V       -51.57mA   -125.6mA   -29.39mA
-950mV    -24.91mA   -88.47mA   -13.14mA
-900mV    -10.56mA   -55.77mA   -8.357mA
-850mV    -5.628mA   -29.91mA   -6.324mA
-800mV    -3.796mA   -13.38mA   -4.704mA
-700mV    -1.746mA   -2.612mA   -2.066mA
-500mV    -57.04uA   -160.7uA   -33.59uA
2.35V     0A         0A         0A
[POWER_clamp]
|Voltage   I(typ)   I(min)   I(max)
-2.4V     1.416A     1.517A     1.357A
-1.26V    314.3mA    421.1mA    251mA
-1.23V    286.6mA    393.5mA    223.3mA
-1.17V    232.1mA    338.6mA    168.9mA
-1.05V    127.5mA    231.7mA    67.38mA
-960mV    57.8mA     155.4mA    12.02mA
-900mV    22.3mA     108mA      1.053mA
-870mV    10.84mA    85.89mA    250.1uA
-810mV    1.516mA    46.81mA    16.91uA
-720mV    52.87uA    10.02mA    3.322uA
-600mV    2.856uA    415.9uA    1.64uA
0V        0A         0A         0A
[Ramp]
| variable   typ   min   max
dV/dt_r  0.74076/59.91265n   0.19152/60.45455n   1.11826/59.99775n
dV/dt_f  0.74088/0.47024u   0.19038/1.36232u   1.11822/0.23129u
R_load = 50.000000
[Rising Waveform]
R_fixture= 50.000000
V_fixture= 2.400000
V_fixture_min= 1.650000
V_fixture_max= 2.700000
|time   V(typ)   V(min)   V(max)
0s        1.165V     1.333V     836.2mV
27.43us   1.165V     1.333V     836.2mV
27.63us   1.165V     1.333V     2.7V
42.04us   1.165V     1.333V     2.7V
42.24us   2.4V       1.333V     2.7V
93.29us   2.4V       1.332V     2.7V
93.49us   2.4V       1.552V     2.7V
93.69us   2.4V       1.649V     2.7V
99.7us    2.4V       1.65V      2.7V
[Falling Waveform]
R_fixture= 50.000000
V_fixture= 2.400000
V_fixture_min= 1.650000
V_fixture_max= 2.700000
|time   V(typ)   V(min)   V(max)
0s        2.4V       1.65V      2.7V
160.2ns   2.4V       1.65V      2.621V
380.4ns   2.281V     1.65V      1.509V
500.5ns   2.135V     1.65V      1.047V
800.8ns   1.611V     1.649V     866.9mV
940.9ns   1.414V     1.648V     852.9mV
1.381us   1.223V     1.626V     837.7mV
1.702us   1.188V     1.584V     836.9mV
3.303us   1.166V     1.371V     836.3mV
9.97us    1.165V     1.333V     836.2mV
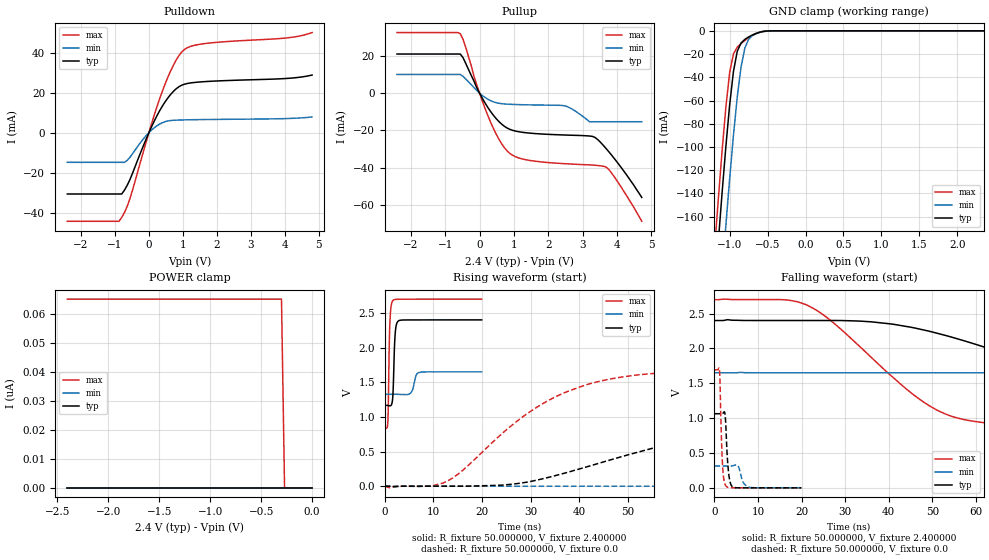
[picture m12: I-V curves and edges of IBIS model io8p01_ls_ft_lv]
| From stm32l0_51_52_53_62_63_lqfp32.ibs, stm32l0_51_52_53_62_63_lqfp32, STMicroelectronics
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|   Model io8p01_ls_ft_lv
[Model]  io8p01_ls_ft_lv
Model_type I/O
Polarity   Non-Inverting
Enable   Active-Low
Vinl =   0.720000V
Vinh =   1.680000V
Vmeas =  1.200000V
Cref =   50.000000pF
Rref =   100.000000M
Vref =   0.0V
C_comp   4.521100pF   4.438000pF   4.578000pF
[Temperature Range]   25.000000   0.105000k   -40.000000
[Pullup Reference]   2.400000V   1.650000V   2.700000V
[Pulldown Reference]   0.0V   0.0V   0.0V
[POWER Clamp Reference]   2.400000V   1.650000V   2.700000V
[GND Clamp Reference]   0.0V   0.0V   0.0V
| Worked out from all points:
|   slope of the pulldown table from 0 to 0.36 V, typ, clamps not added: 29.5 ohm
|   slope of the pullup table from 0 to 0.36 V, typ, clamps not added: 33.2 ohm
|   GND clamp passes 1 mA (typ) near -0.59 V on its own axis
|   rising waveform, R_fixture 50.000000, V_fixture 2.400000: 20-80 % time 360ps typ, 683ps min, 299ps max; typ from 1.17 V to 2.4 V
|   rising waveform, R_fixture 50.000000, V_fixture 0.0: 20-80 % time 39.5ns typ, 107ns min, 19.4ns max; typ from 0 V to 1.06 V
|   falling waveform, R_fixture 50.000000, V_fixture 2.400000: 20-80 % time 41.1ns typ, 105ns min, 20.5ns max; typ from 2.4 V to 1.17 V
|   falling waveform, R_fixture 50.000000, V_fixture 0.0: 20-80 % time 616ps typ, 985ps min, 510ps max; typ from 1.06 V to 0 V
[Pulldown]
|Voltage   I(typ)   I(min)   I(max)
-2.4V     -30.64mA   -14.84mA   -44.29mA
-880mV    -30.64mA   -14.84mA   -44.29mA
-800mV    -30.64mA   -14.84mA   -42.37mA
-560mV    -23.52mA   -12.34mA   -33.09mA
0V        -765.2nA   -61.1nA    -2.527uA
400mV     13.38mA    4.998mA    20.91mA
720mV     20.62mA    6.178mA    33.69mA
880mV     22.92mA    6.307mA    38.42mA
1.04V     24.19mA    6.385mA    41.49mA
1.6V      25.46mA    6.544mA    44.42mA
4V        27.04mA    7.029mA    47.25mA
4.8V      28.77mA    7.818mA    50.02mA
[Pullup]
|Voltage   I(typ)   I(min)   I(max)
-2.4V     21.03mA    10.05mA    32.57mA
-560mV    21.03mA    10.05mA    32mA
-400mV    15.95mA    7.623mA    24.54mA
240mV     -7.653mA   -3.251mA   -12mA
560mV     -15.22mA   -5.43mA    -24.63mA
800mV     -18.73mA   -5.909mA   -31mA
1.28V     -21.13mA   -6.237mA   -35.54mA
2.48V     -22.51mA   -6.82mA    -37.93mA
3.2V      -23.05mA   -15.37mA   -38.57mA
3.36V     -23.83mA   -15.37mA   -38.77mA
3.76V     -31.5mA    -15.37mA   -41.06mA
4.72V     -56.1mA    -15.37mA   -68.9mA
[GND_clamp]
|Voltage   I(typ)   I(min)   I(max)
-2.4V     -1.379A    -1.445A    -1.35A
-1.2V     -225.9mA   -297.5mA   -189.2mA
-1.15V    -182mA     -253.1mA   -145.3mA
-1.1V     -139.6mA   -209.7mA   -103.5mA
-1.05V    -99.61mA   -167.6mA   -65.7mA
-1V       -63.67mA   -127.3mA   -35.89mA
-950mV    -35mA      -89.93mA   -19.87mA
-900mV    -17.67mA   -57.01mA   -14.12mA
-850mV    -10.49mA   -31.18mA   -11mA
-750mV    -5.288mA   -7.322mA   -5.997mA
-450mV    -33.57uA   -87.56uA   -14.35uA
2.35V     0A         0A         0A
[POWER_clamp]
|Voltage   I(typ)   I(min)   I(max)
-2.4V     0A         0A         65.17nA
-300mV    0A         0A         65.17nA
-270mV    0A         0A         0A
0V        0A         0A         0A
[Ramp]
| variable   typ   min   max
dV/dt_r  0.63779/39.41460n   0.18764/0.10659u   1.01572/19.35472n
dV/dt_f  0.74034/41.02678n   0.19224/0.10508u   1.11789/20.44182n
R_load = 50.000000
[Rising Waveform]
R_fixture= 50.000000
V_fixture= 2.400000
V_fixture_min= 1.650000
V_fixture_max= 2.700000
|time   V(typ)   V(min)   V(max)
0s        1.166V     1.326V     836.3mV
640.6ps   1.165V     1.326V     938.9mV
920.9ps   1.161V     1.326V     2.046V
1.041ns   1.16V      1.326V     2.337V
1.642ns   1.285V     1.326V     2.676V
2.122ns   2.182V     1.326V     2.695V
2.763ns   2.382V     1.326V     2.698V
5.285ns   2.399V     1.342V     2.699V
7.207ns   2.4V       1.643V     2.7V
19.94ns   2.4V       1.65V      2.7V
[Rising Waveform]
R_fixture= 50.000000
V_fixture= 0.0
V_fixture_min= 0.0
V_fixture_max= 0.0
|time   V(typ)   V(min)   V(max)
0s        55.18uV    17uV       479.9uV
13.01ns   -207.6uV   -47.12uV   78.88mV
28.03ns   44.65mV    -46.38uV   981.9mV
38.04ns   208.2mV    -46.83uV   1.378V
49.05ns   432.1mV    -37.31uV   1.578V
64.06ns   692.2mV    25.52uV    1.664V
89.09ns   933.4mV    1.575mV    1.69V
127.1ns   1.041V     48.34mV    1.693V
254.3ns   1.063V     264.2mV    1.693V
498.5ns   1.063V     313mV      1.693V
[Falling Waveform]
R_fixture= 50.000000
V_fixture= 2.400000
V_fixture_min= 1.650000
V_fixture_max= 2.700000
|time   V(typ)   V(min)   V(max)
0s        2.4V       1.65V      2.7V
21.02ns   2.4V       1.65V      2.627V
36.04ns   2.381V     1.65V      1.869V
51.05ns   2.218V     1.65V      1.116V
58.06ns   2.095V     1.65V      969.8mV
71.07ns   1.83V      1.65V      890mV
100.1ns   1.376V     1.65V      847.6mV
146.1ns   1.211V     1.628V     837.6mV
282.3ns   1.167V     1.389V     836.3mV
498.5ns   1.166V     1.326V     836.3mV
[Falling Waveform]
R_fixture= 50.000000
V_fixture= 0.0
V_fixture_min= 0.0
V_fixture_max= 0.0
|time   V(typ)   V(min)   V(max)
0s        1.063V     313mV      1.693V
1.121ns   1.063V     313mV      1.705V
1.842ns   1.065V     313mV      335.6mV
2.362ns   1.077V     313mV      62.09mV
2.643ns   838.2mV    313mV      25.56mV
3.203ns   238.4mV    312.7mV    5.061mV
4.084ns   18.93mV    315.5mV    1.661mV
5.405ns   770uV      317.3mV    1.103mV
7.728ns   183.9uV    13.64mV    760.5uV
19.94ns   55.18uV    17uV       479.9uV
